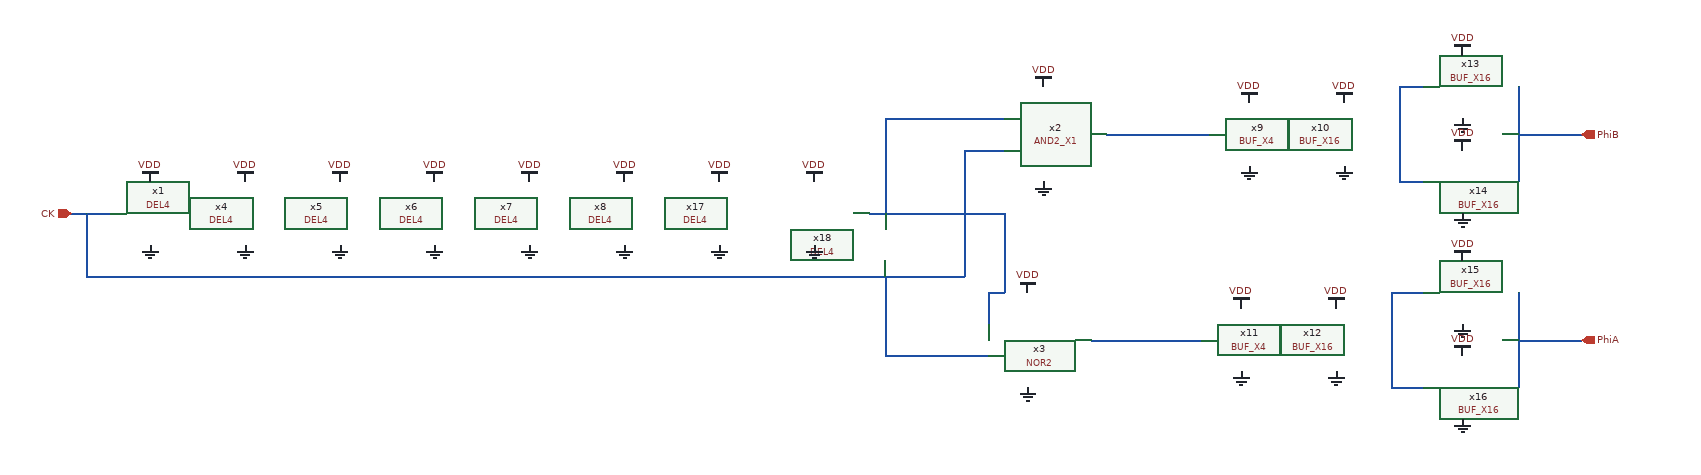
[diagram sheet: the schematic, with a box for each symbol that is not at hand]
v {xschem version=3.4.8RC file_version=1.3}
G {}
K {}
V {}
S {}
F {}
E {}
N 410 -130 410 20 {lab=CK}
N 410 -130 460 -130 {lab=CK}
N 590 -150 720 -150 {lab=#net1}
N 570 110 710 110 {lab=#net2}
N 1110 -150 1150 -150 {lab=PhiB}
N 1150 -150 1190 -150 {lab=PhiB}
N 1110 110 1160 110 {lab=PhiA}
N 1160 110 1190 110 {lab=PhiA}
N 960 -210 960 -150 {lab=#net3}
N 960 -210 990 -210 {lab=#net3}
N 960 -150 960 -90 {lab=#net3}
N 960 -90 990 -90 {lab=#net3}
N 950 50 950 110 {lab=#net4}
N 950 50 990 50 {lab=#net4}
N 950 110 950 170 {lab=#net4}
N 950 170 990 170 {lab=#net4}
N 1110 -210 1110 -90 {lab=PhiB}
N 1110 50 1110 170 {lab=PhiA}
N -720 -50 -670 -50 {lab=CK}
N -700 -50 -700 30 {lab=CK}
N -700 30 360 30 {lab=CK}
N 360 30 410 30 {lab=CK}
N 410 20 410 30 {lab=CK}
N 310 130 440 130 {lab=CK}
N 310 30 310 130 {lab=CK}
N 290 -50 360 -50 {lab=#net5}
N 310 -170 310 -50 {lab=#net5}
N 310 -170 460 -170 {lab=#net5}
N 360 -50 460 -50 {lab=#net5}
N 460 -50 460 50 {lab=#net5}
N 440 50 460 50 {lab=#net5}
N 440 50 440 90 {lab=#net5}
C {TR-1um_5_stdcell/AND2_X1.sym} 480 -150 0 0 {name=x2}
C {TR-1um_5_stdcell/NOR2.sym} 460 110 0 0 {name=x3}
C {TR-1um_5_stdcell/BUF_X4.sym} 740 -150 0 0 {name=x9}
C {TR-1um_5_stdcell/BUF_X16.sym} 860 -150 0 0 {name=x10}
C {TR-1um_5_stdcell/BUF_X4.sym} 730 110 0 0 {name=x11}
C {TR-1um_5_stdcell/BUF_X16.sym} 850 110 0 0 {name=x12}
C {TR-1um_5_stdcell/BUF_X16.sym} 1010 -210 0 0 {name=x13}
C {TR-1um_5_stdcell/BUF_X16.sym} 1010 -90 0 0 {name=x14}
C {devices/gnd.sym} 1040 -170 0 0 {name=l3 lab=GND}
C {devices/gnd.sym} 1040 -50 0 0 {name=l9 lab=GND
}
C {TR-1um_5_stdcell/BUF_X16.sym} 1010 50 0 0 {name=x15}
C {TR-1um_5_stdcell/BUF_X16.sym} 1010 170 0 0 {name=x16}
C {devices/gnd.sym} 1040 90 0 0 {name=l10 lab=GND}
C {TR-1um_5_stdcell/DEL4.sym} -650 -50 0 0 {name=x1}
C {TR-1um_5_stdcell/DEL4.sym} -530 -50 0 0 {name=x4}
C {TR-1um_5_stdcell/DEL4.sym} -410 -50 0 0 {name=x5}
C {TR-1um_5_stdcell/DEL4.sym} -290 -50 0 0 {name=x6}
C {TR-1um_5_stdcell/DEL4.sym} -170 -50 0 0 {name=x7}
C {TR-1um_5_stdcell/DEL4.sym} -50 -50 0 0 {name=x8}
C {TR-1um_5_stdcell/DEL4.sym} 70 -50 0 0 {name=x17}
C {TR-1um_5_stdcell/DEL4.sym} 190 -50 0 0 {name=x18}
C {devices/gnd.sym} -620 -10 0 0 {name=l1 lab=GND}
C {devices/gnd.sym} -500 -10 0 0 {name=l12 lab=GND}
C {devices/gnd.sym} -380 -10 0 0 {name=l13 lab=GND}
C {devices/gnd.sym} -260 -10 0 0 {name=l14 lab=GND}
C {devices/gnd.sym} -140 -10 0 0 {name=l15 lab=GND}
C {devices/gnd.sym} -20 -10 0 0 {name=l16 lab=GND}
C {devices/gnd.sym} 100 -10 0 0 {name=l17 lab=GND}
C {devices/gnd.sym} 220 -10 0 0 {name=l18 lab=GND}
C {devices/vdd.sym} -620 -90 0 0 {name=l19 lab=VDD}
C {devices/vdd.sym} -500 -90 0 0 {name=l20 lab=VDD}
C {devices/vdd.sym} -380 -90 0 0 {name=l21 lab=VDD}
C {devices/vdd.sym} -260 -90 0 0 {name=l22 lab=VDD}
C {devices/vdd.sym} -140 -90 0 0 {name=l23 lab=VDD}
C {devices/vdd.sym} -20 -90 0 0 {name=l24 lab=VDD}
C {devices/vdd.sym} 100 -90 0 0 {name=l25 lab=VDD}
C {devices/vdd.sym} 220 -90 0 0 {name=l26 lab=VDD}
C {devices/vdd.sym} 510 -210 0 0 {name=l29 lab=VDD}
C {devices/vdd.sym} 770 -190 0 0 {name=l30 lab=VDD}
C {devices/vdd.sym} 890 -190 0 0 {name=l31 lab=VDD}
C {devices/vdd.sym} 1040 -130 0 0 {name=l32 lab=VDD}
C {devices/vdd.sym} 880 70 0 0 {name=l33 lab=VDD}
C {devices/vdd.sym} 760 70 0 0 {name=l34 lab=VDD}
C {devices/vdd.sym} 490 50 0 0 {name=l35 lab=VDD}
C {devices/vdd.sym} 1040 10 0 0 {name=l36 lab=VDD}
C {devices/vdd.sym} 1040 130 0 0 {name=l37 lab=VDD}
C {devices/ipin.sym} -720 -50 0 0 {name=p2 lab=CK}
C {devices/opin.sym} 1190 -150 0 0 {name=p3 lab=PhiB}
C {devices/opin.sym} 1190 110 0 0 {name=p1 lab=PhiA}
C {devices/vdd.sym} 1040 -250 0 0 {name=l2 lab=VDD}
C {devices/gnd.sym} 1040 210 0 0 {name=l4 lab=GND
}
C {devices/gnd.sym} 880 150 0 0 {name=l5 lab=GND
}
C {devices/gnd.sym} 890 -110 0 0 {name=l6 lab=GND
}
C {devices/gnd.sym} 770 -110 0 0 {name=l7 lab=GND
}
C {devices/gnd.sym} 760 150 0 0 {name=l8 lab=GND
}
C {devices/gnd.sym} 490 170 0 0 {name=l11 lab=GND
}
C {devices/gnd.sym} 510 -90 0 0 {name=l27 lab=GND
}
